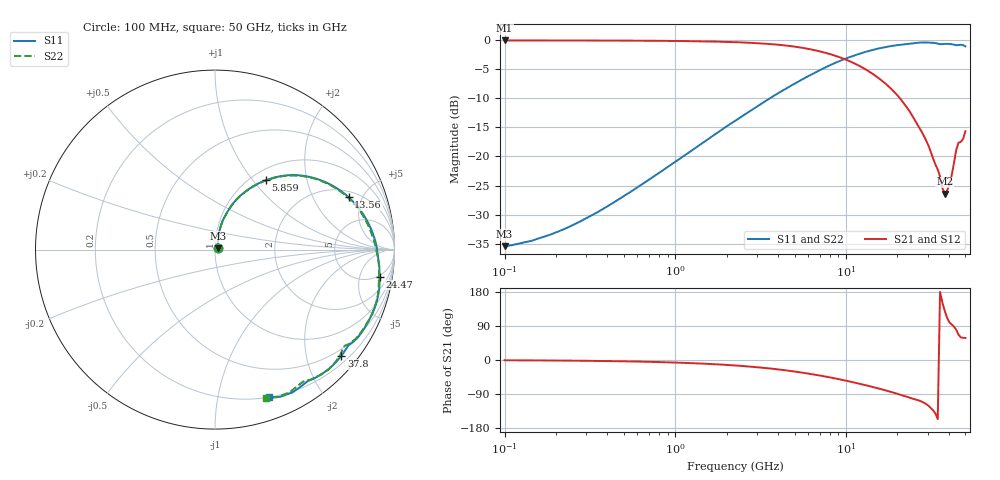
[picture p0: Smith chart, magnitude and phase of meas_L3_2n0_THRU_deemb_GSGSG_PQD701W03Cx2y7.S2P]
!  2-Port S-parameters saved by WinCal
! VAR NAME=L3_THRU_deemb
! VAR ObjTypeName=DATASET
! VAR IndexType=Frequency
! VAR FILENAME=L3_2n0_THRU_deemb_GSGSG.S2P
# Hz S RI R 50
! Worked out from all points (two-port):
!   201 points, 100 MHz to 50 GHz, reference 50 ohm
!   highest |S21| = -0.13 dB at 100 MHz (marker M1); lowest = -26.4 dB at 37.8 GHz (marker M2)
!   |S21| within 3 dB of the highest: start of sweep to 9.416 GHz
!   lowest |S11| = -35.4 dB at 100 MHz (marker M3), VSWR 1.03, Z = 51.5 + j0.845 ohm
!   |S11| at or under -10 dB: start of sweep to 3.599 GHz
!   |S22| runs from -35.4 to -0.5 dB; largest |S21 - S12| = 0.00048
!   S11 on the Smith chart (normalised r, x): 100 MHz: 1.03, +0.02; 5.859 GHz: 1.16, +1.16; 13.56 GHz: 2.40, +3.89; 24.47 GHz: 5, -10; 37.8 GHz: 0.35, -2.70; 50 GHz: 0.20, -1.41
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1e8  0.0149 0.0082  0.985 -0.0122  0.9848 -0.012  0.0148 0.00819
1.804688e8  0.0148 0.015  0.9845 -0.0216  0.9843 -0.0216  0.0147 0.015
2.876239e8  0.0148 0.0244  0.9836 -0.0342  0.9833 -0.0342  0.0148 0.0244
8.019641e8  0.0184 0.0698  0.974 -0.0928  0.9738 -0.0928  0.0185 0.0697
2.236068e9  0.0588 0.1925  0.9226 -0.2369  0.9225 -0.2369  0.0591 0.1922
3.792254e9  0.1411 0.3002  0.8358 -0.3647  0.8357 -0.3646  0.1412 0.2991
5.859025e9  0.2818 0.386  0.6877 -0.483  0.6875 -0.483  0.2824 0.3848
6.431465e9  0.3224 0.3993  0.6441 -0.5041  0.6439 -0.504  0.3232 0.3979
9.632587e9  0.5446 0.4007  0.4143 -0.55  0.4142 -0.55  0.5454 0.3981
1.355771e10  0.7449 0.2915  0.1969 -0.4991  0.1968 -0.4991  0.745 0.2864
1.793246e10  0.8691 0.1152  0.0477 -0.3896  0.0476 -0.3896  0.8649 0.108
2.446744e10  0.9168 -0.1499  -0.0454 -0.2174  -0.0454 -0.2173  0.9137 -0.1584
3.041252e10  0.8614 -0.3868  -0.0633 -0.1058  -0.0634 -0.1057  0.8533 -0.3993
3.443751e10  0.7699 -0.5144  -0.0705 -0.0314  -0.0705 -0.0314  0.751 -0.5245
3.664557e10  0.7263 -0.5589  -0.0475 0.025  -0.0475 0.0251  0.7115 -0.5548
3.780214e10  0.7038 -0.5925  -0.031 0.0365  -0.031 0.0365  0.6953 -0.5917
4.022593e10  0.6406 -0.6598  -0.00969 0.0564  -0.00965 0.0565  0.6313 -0.6689
4.149549e10  0.6006 -0.6897  -0.0046 0.0677  -0.00463 0.0677  0.5849 -0.7
4.415609e10  0.5152 -0.7334  0.0193 0.1113  0.0194 0.1113  0.4922 -0.7343
4.554969e10  0.4813 -0.7608  0.0516 0.1204  0.0515 0.1203  0.4627 -0.7579
4.847024e10  0.3646 -0.8197  0.0736 0.1202  0.0736 0.1202  0.3478 -0.8222
5e10  0.3024 -0.8236  0.0866 0.1397  0.0866 0.1395  0.2835 -0.8267
